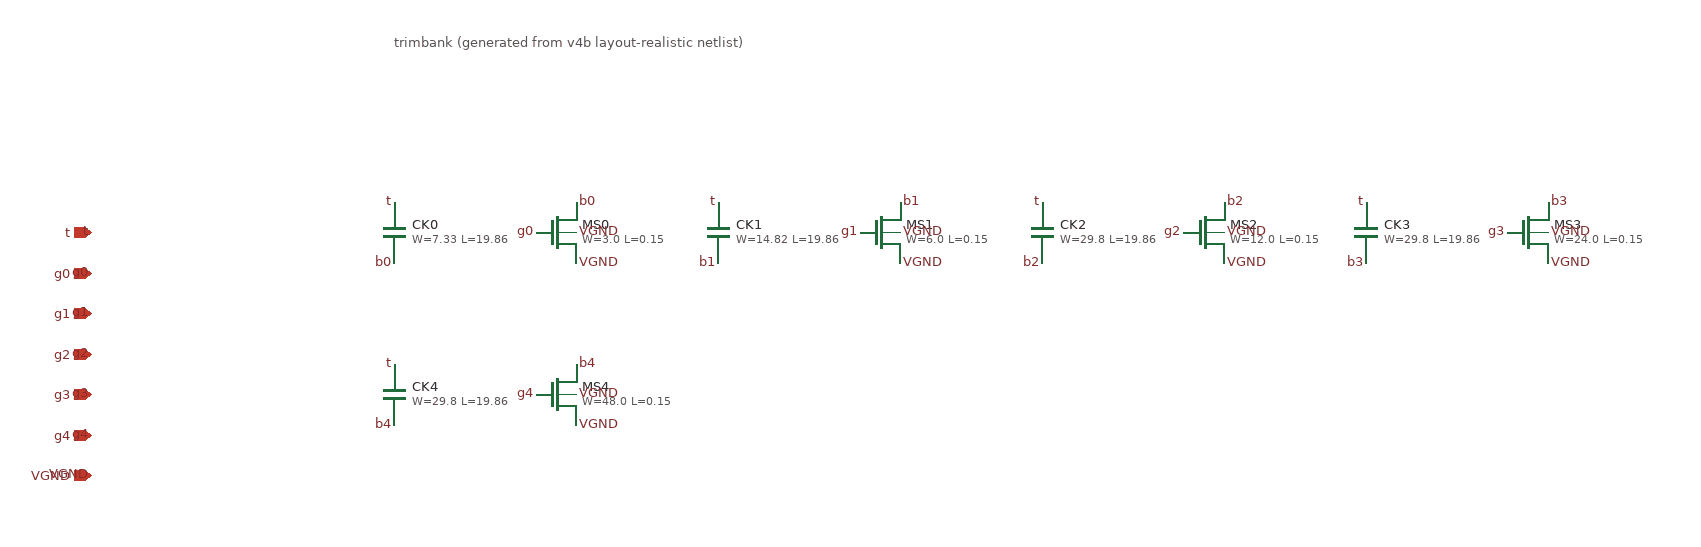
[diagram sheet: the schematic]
v {xschem version=3.4.8RC file_version=1.2}
G {}
K {}
V {}
S {}
E {}
T {trimbank  (generated from v4b layout-realistic netlist)} 0 -200 0 0 0.4 0.4 {}
C {iopin.sym} -300 0 0 0 {name=l1 sig_type=std_logic lab=t}
C {iopin.sym} -300 40 0 0 {name=l2 sig_type=std_logic lab=g0}
C {iopin.sym} -300 80 0 0 {name=l3 sig_type=std_logic lab=g1}
C {iopin.sym} -300 120 0 0 {name=l4 sig_type=std_logic lab=g2}
C {iopin.sym} -300 160 0 0 {name=l5 sig_type=std_logic lab=g3}
C {iopin.sym} -300 200 0 0 {name=l6 sig_type=std_logic lab=g4}
C {iopin.sym} -300 240 0 0 {name=l7 sig_type=std_logic lab=VGND}
C {lab_pin.sym} -300 0 0 0 {name=l8 sig_type=std_logic lab=t}
C {lab_pin.sym} -300 40 0 0 {name=l9 sig_type=std_logic lab=g0}
C {lab_pin.sym} -300 80 0 0 {name=l10 sig_type=std_logic lab=g1}
C {lab_pin.sym} -300 120 0 0 {name=l11 sig_type=std_logic lab=g2}
C {lab_pin.sym} -300 160 0 0 {name=l12 sig_type=std_logic lab=g3}
C {lab_pin.sym} -300 200 0 0 {name=l13 sig_type=std_logic lab=g4}
C {lab_pin.sym} -300 240 0 0 {name=l14 sig_type=std_logic lab=VGND}
C {sky130_fd_pr/cap_mim_m3_1.sym} 0 0 0 0 {name=CK0 model=cap_mim_m3_1 W=7.33 L=19.86 MF=1 spiceprefix=X}
C {lab_pin.sym} 0 -30 0 0 {name=l15 sig_type=std_logic lab=t}
C {lab_pin.sym} 0 30 0 0 {name=l16 sig_type=std_logic lab=b0}
C {sky130_fd_pr/nfet_01v8.sym} 160 0 0 0 {name=MS0 W=3.0 L=0.15 nf=1 mult=1 model=nfet_01v8 spiceprefix=X}
C {lab_pin.sym} 180 -30 0 1 {name=l17 sig_type=std_logic lab=b0}
C {lab_pin.sym} 140 0 0 0 {name=l18 sig_type=std_logic lab=g0}
C {lab_pin.sym} 180 30 0 1 {name=l19 sig_type=std_logic lab=VGND}
C {lab_pin.sym} 180 0 0 1 {name=l20 sig_type=std_logic lab=VGND}
C {sky130_fd_pr/cap_mim_m3_1.sym} 320 0 0 0 {name=CK1 model=cap_mim_m3_1 W=14.82 L=19.86 MF=1 spiceprefix=X}
C {lab_pin.sym} 320 -30 0 0 {name=l21 sig_type=std_logic lab=t}
C {lab_pin.sym} 320 30 0 0 {name=l22 sig_type=std_logic lab=b1}
C {sky130_fd_pr/nfet_01v8.sym} 480 0 0 0 {name=MS1 W=6.0 L=0.15 nf=1 mult=1 model=nfet_01v8 spiceprefix=X}
C {lab_pin.sym} 500 -30 0 1 {name=l23 sig_type=std_logic lab=b1}
C {lab_pin.sym} 460 0 0 0 {name=l24 sig_type=std_logic lab=g1}
C {lab_pin.sym} 500 30 0 1 {name=l25 sig_type=std_logic lab=VGND}
C {lab_pin.sym} 500 0 0 1 {name=l26 sig_type=std_logic lab=VGND}
C {sky130_fd_pr/cap_mim_m3_1.sym} 640 0 0 0 {name=CK2 model=cap_mim_m3_1 W=29.8 L=19.86 MF=1 spiceprefix=X}
C {lab_pin.sym} 640 -30 0 0 {name=l27 sig_type=std_logic lab=t}
C {lab_pin.sym} 640 30 0 0 {name=l28 sig_type=std_logic lab=b2}
C {sky130_fd_pr/nfet_01v8.sym} 800 0 0 0 {name=MS2 W=12.0 L=0.15 nf=1 mult=1 model=nfet_01v8 spiceprefix=X}
C {lab_pin.sym} 820 -30 0 1 {name=l29 sig_type=std_logic lab=b2}
C {lab_pin.sym} 780 0 0 0 {name=l30 sig_type=std_logic lab=g2}
C {lab_pin.sym} 820 30 0 1 {name=l31 sig_type=std_logic lab=VGND}
C {lab_pin.sym} 820 0 0 1 {name=l32 sig_type=std_logic lab=VGND}
C {sky130_fd_pr/cap_mim_m3_1.sym} 960 0 0 0 {name=CK3 model=cap_mim_m3_1 W=29.8 L=19.86 MF=2 spiceprefix=X}
C {lab_pin.sym} 960 -30 0 0 {name=l33 sig_type=std_logic lab=t}
C {lab_pin.sym} 960 30 0 0 {name=l34 sig_type=std_logic lab=b3}
C {sky130_fd_pr/nfet_01v8.sym} 1120 0 0 0 {name=MS3 W=24.0 L=0.15 nf=1 mult=1 model=nfet_01v8 spiceprefix=X}
C {lab_pin.sym} 1140 -30 0 1 {name=l35 sig_type=std_logic lab=b3}
C {lab_pin.sym} 1100 0 0 0 {name=l36 sig_type=std_logic lab=g3}
C {lab_pin.sym} 1140 30 0 1 {name=l37 sig_type=std_logic lab=VGND}
C {lab_pin.sym} 1140 0 0 1 {name=l38 sig_type=std_logic lab=VGND}
C {sky130_fd_pr/cap_mim_m3_1.sym} 0 160 0 0 {name=CK4 model=cap_mim_m3_1 W=29.8 L=19.86 MF=4 spiceprefix=X}
C {lab_pin.sym} 0 130 0 0 {name=l39 sig_type=std_logic lab=t}
C {lab_pin.sym} 0 190 0 0 {name=l40 sig_type=std_logic lab=b4}
C {sky130_fd_pr/nfet_01v8.sym} 160 160 0 0 {name=MS4 W=48.0 L=0.15 nf=1 mult=1 model=nfet_01v8 spiceprefix=X}
C {lab_pin.sym} 180 130 0 1 {name=l41 sig_type=std_logic lab=b4}
C {lab_pin.sym} 140 160 0 0 {name=l42 sig_type=std_logic lab=g4}
C {lab_pin.sym} 180 190 0 1 {name=l43 sig_type=std_logic lab=VGND}
C {lab_pin.sym} 180 160 0 1 {name=l44 sig_type=std_logic lab=VGND}
